# ------------------------------------------------------
#
#		Copyright 2025 IHP PDK Authors
#
#		Licensed under the Apache License, Version 2.0 (the "License");
#		you may not use this file except in compliance with the License.
#		You may obtain a copy of the License at
#		
#		   https://www.apache.org/licenses/LICENSE-2.0
#		
#		Unless required by applicable law or agreed to in writing, software
#		distributed under the License is distributed on an "AS IS" BASIS,
#		WITHOUT WARRANTIES OR CONDITIONS OF ANY KIND, either express or implied.
#		See the License for the specific language governing permissions and
#		limitations under the License.
#		
#		Generated on Thu Jul 30 11:38:32 2026		
#
# ------------------------------------------------------ 
VERSION 5.7 ;
BUSBITCHARS "[]" ;
DIVIDERCHAR "/" ;

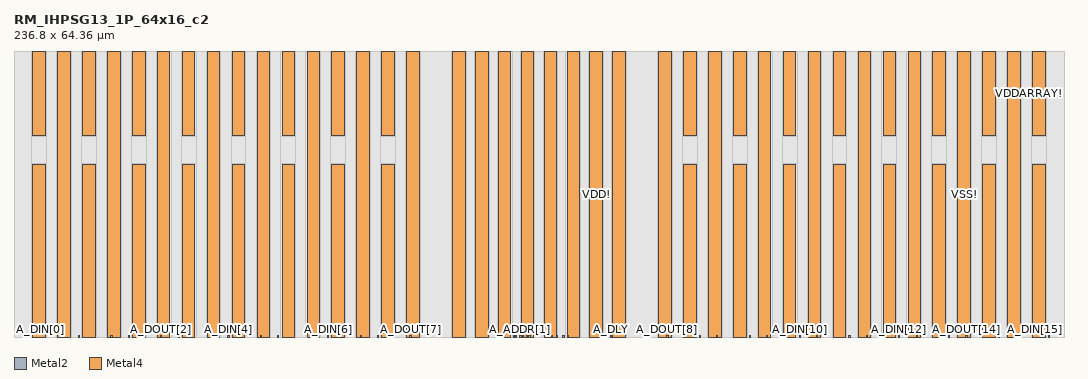
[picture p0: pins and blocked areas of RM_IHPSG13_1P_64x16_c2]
MACRO RM_IHPSG13_1P_64x16_c2
  CLASS BLOCK ;
  ORIGIN 0 0 ;
  FOREIGN RM_IHPSG13_1P_64x16_c2 0 0 ;
  SIZE 236.8 BY 64.36 ;
  SYMMETRY X Y R90 ;
  PIN A_DIN[8]
    DIRECTION INPUT ;
    USE SIGNAL ;
    ANTENNAPARTIALMETALAREA 1.794 LAYER Metal2 ;
    ANTENNAMODEL OXIDE1 ;
      ANTENNAGATEAREA 0.20085 LAYER Metal2 ;
      ANTENNAMAXAREACAR 9.838188 LAYER Metal2 ;
    PORT
      LAYER Metal2 ;
        RECT 154.57 0 154.83 0.26 ;
    END
  END A_DIN[8]
  PIN A_DIN[7]
    DIRECTION INPUT ;
    USE SIGNAL ;
    ANTENNAPARTIALMETALAREA 1.794 LAYER Metal2 ;
    ANTENNAMODEL OXIDE1 ;
      ANTENNAGATEAREA 0.20085 LAYER Metal2 ;
      ANTENNAMAXAREACAR 9.838188 LAYER Metal2 ;
    PORT
      LAYER Metal2 ;
        RECT 81.97 0 82.23 0.26 ;
    END
  END A_DIN[7]
  PIN A_DOUT[8]
    DIRECTION OUTPUT ;
    USE SIGNAL ;
    ANTENNAPARTIALMETALAREA 3.7095 LAYER Metal2 ;
    ANTENNADIFFAREA 0.988 LAYER Metal2 ;
    PORT
      LAYER Metal2 ;
        RECT 147.24 0 147.5 0.26 ;
    END
  END A_DOUT[8]
  PIN A_DOUT[7]
    DIRECTION OUTPUT ;
    USE SIGNAL ;
    ANTENNAPARTIALMETALAREA 3.7095 LAYER Metal2 ;
    ANTENNADIFFAREA 0.988 LAYER Metal2 ;
    PORT
      LAYER Metal2 ;
        RECT 89.3 0 89.56 0.26 ;
    END
  END A_DOUT[7]
  PIN VSS!
    DIRECTION INOUT ;
    USE GROUND ;
    NETEXPR "vss VSS!" ;
    PORT
      LAYER Metal4 ;
        RECT 224.11 0 226.92 64.36 ;
    END
    PORT
      LAYER Metal4 ;
        RECT 212.87 0 215.68 64.36 ;
    END
    PORT
      LAYER Metal4 ;
        RECT 201.63 0 204.44 64.36 ;
    END
    PORT
      LAYER Metal4 ;
        RECT 190.39 0 193.2 64.36 ;
    END
    PORT
      LAYER Metal4 ;
        RECT 179.15 0 181.96 64.36 ;
    END
    PORT
      LAYER Metal4 ;
        RECT 167.91 0 170.72 64.36 ;
    END
    PORT
      LAYER Metal4 ;
        RECT 156.67 0 159.48 64.36 ;
    END
    PORT
      LAYER Metal4 ;
        RECT 145.43 0 148.24 64.36 ;
    END
    PORT
      LAYER Metal4 ;
        RECT 135.02 0 137.83 64.36 ;
    END
    PORT
      LAYER Metal4 ;
        RECT 124.72 0 127.53 64.36 ;
    END
    PORT
      LAYER Metal4 ;
        RECT 109.27 0 112.08 64.36 ;
    END
    PORT
      LAYER Metal4 ;
        RECT 98.97 0 101.78 64.36 ;
    END
    PORT
      LAYER Metal4 ;
        RECT 88.56 0 91.37 64.36 ;
    END
    PORT
      LAYER Metal4 ;
        RECT 77.32 0 80.13 64.36 ;
    END
    PORT
      LAYER Metal4 ;
        RECT 66.08 0 68.89 64.36 ;
    END
    PORT
      LAYER Metal4 ;
        RECT 54.84 0 57.65 64.36 ;
    END
    PORT
      LAYER Metal4 ;
        RECT 43.6 0 46.41 64.36 ;
    END
    PORT
      LAYER Metal4 ;
        RECT 32.36 0 35.17 64.36 ;
    END
    PORT
      LAYER Metal4 ;
        RECT 21.12 0 23.93 64.36 ;
    END
    PORT
      LAYER Metal4 ;
        RECT 9.88 0 12.69 64.36 ;
    END
  END VSS!
  PIN VDD!
    DIRECTION INOUT ;
    USE POWER ;
    NETEXPR "vdd VDD!" ;
    PORT
      LAYER Metal4 ;
        RECT 229.73 0 232.54 38.825 ;
    END
    PORT
      LAYER Metal4 ;
        RECT 218.49 0 221.3 38.825 ;
    END
    PORT
      LAYER Metal4 ;
        RECT 207.25 0 210.06 38.825 ;
    END
    PORT
      LAYER Metal4 ;
        RECT 196.01 0 198.82 38.825 ;
    END
    PORT
      LAYER Metal4 ;
        RECT 184.77 0 187.58 38.825 ;
    END
    PORT
      LAYER Metal4 ;
        RECT 173.53 0 176.34 38.825 ;
    END
    PORT
      LAYER Metal4 ;
        RECT 162.29 0 165.1 38.825 ;
    END
    PORT
      LAYER Metal4 ;
        RECT 151.05 0 153.86 38.825 ;
    END
    PORT
      LAYER Metal4 ;
        RECT 129.87 0 132.68 64.36 ;
    END
    PORT
      LAYER Metal4 ;
        RECT 119.57 0 122.38 64.36 ;
    END
    PORT
      LAYER Metal4 ;
        RECT 114.42 0 117.23 64.36 ;
    END
    PORT
      LAYER Metal4 ;
        RECT 104.12 0 106.93 64.36 ;
    END
    PORT
      LAYER Metal4 ;
        RECT 82.94 0 85.75 38.825 ;
    END
    PORT
      LAYER Metal4 ;
        RECT 71.7 0 74.51 38.825 ;
    END
    PORT
      LAYER Metal4 ;
        RECT 60.46 0 63.27 38.825 ;
    END
    PORT
      LAYER Metal4 ;
        RECT 49.22 0 52.03 38.825 ;
    END
    PORT
      LAYER Metal4 ;
        RECT 37.98 0 40.79 38.825 ;
    END
    PORT
      LAYER Metal4 ;
        RECT 26.74 0 29.55 38.825 ;
    END
    PORT
      LAYER Metal4 ;
        RECT 15.5 0 18.31 38.825 ;
    END
    PORT
      LAYER Metal4 ;
        RECT 4.26 0 7.07 38.825 ;
    END
  END VDD!
  PIN VDDARRAY!
    DIRECTION INOUT ;
    USE POWER ;
    NETEXPR "vddarray VDDARRAY!" ;
    PORT
      LAYER Metal4 ;
        RECT 229.73 45.465 232.54 64.36 ;
    END
    PORT
      LAYER Metal4 ;
        RECT 218.49 45.465 221.3 64.36 ;
    END
    PORT
      LAYER Metal4 ;
        RECT 207.25 45.465 210.06 64.36 ;
    END
    PORT
      LAYER Metal4 ;
        RECT 196.01 45.465 198.82 64.36 ;
    END
    PORT
      LAYER Metal4 ;
        RECT 184.77 45.465 187.58 64.36 ;
    END
    PORT
      LAYER Metal4 ;
        RECT 173.53 45.465 176.34 64.36 ;
    END
    PORT
      LAYER Metal4 ;
        RECT 162.29 45.465 165.1 64.36 ;
    END
    PORT
      LAYER Metal4 ;
        RECT 151.05 45.465 153.86 64.36 ;
    END
    PORT
      LAYER Metal4 ;
        RECT 82.94 45.465 85.75 64.36 ;
    END
    PORT
      LAYER Metal4 ;
        RECT 71.7 45.465 74.51 64.36 ;
    END
    PORT
      LAYER Metal4 ;
        RECT 60.46 45.465 63.27 64.36 ;
    END
    PORT
      LAYER Metal4 ;
        RECT 49.22 45.465 52.03 64.36 ;
    END
    PORT
      LAYER Metal4 ;
        RECT 37.98 45.465 40.79 64.36 ;
    END
    PORT
      LAYER Metal4 ;
        RECT 26.74 45.465 29.55 64.36 ;
    END
    PORT
      LAYER Metal4 ;
        RECT 15.5 45.465 18.31 64.36 ;
    END
    PORT
      LAYER Metal4 ;
        RECT 4.26 45.465 7.07 64.36 ;
    END
  END VDDARRAY!
  PIN A_DIN[9]
    DIRECTION INPUT ;
    USE SIGNAL ;
    ANTENNAPARTIALMETALAREA 1.794 LAYER Metal2 ;
    ANTENNAMODEL OXIDE1 ;
      ANTENNAGATEAREA 0.20085 LAYER Metal2 ;
      ANTENNAMAXAREACAR 9.838188 LAYER Metal2 ;
    PORT
      LAYER Metal2 ;
        RECT 165.81 0 166.07 0.26 ;
    END
  END A_DIN[9]
  PIN A_DIN[6]
    DIRECTION INPUT ;
    USE SIGNAL ;
    ANTENNAPARTIALMETALAREA 1.794 LAYER Metal2 ;
    ANTENNAMODEL OXIDE1 ;
      ANTENNAGATEAREA 0.20085 LAYER Metal2 ;
      ANTENNAMAXAREACAR 9.838188 LAYER Metal2 ;
    PORT
      LAYER Metal2 ;
        RECT 70.73 0 70.99 0.26 ;
    END
  END A_DIN[6]
  PIN A_DOUT[9]
    DIRECTION OUTPUT ;
    USE SIGNAL ;
    ANTENNAPARTIALMETALAREA 3.7095 LAYER Metal2 ;
    ANTENNADIFFAREA 0.988 LAYER Metal2 ;
    PORT
      LAYER Metal2 ;
        RECT 158.48 0 158.74 0.26 ;
    END
  END A_DOUT[9]
  PIN A_DOUT[6]
    DIRECTION OUTPUT ;
    USE SIGNAL ;
    ANTENNAPARTIALMETALAREA 3.7095 LAYER Metal2 ;
    ANTENNADIFFAREA 0.988 LAYER Metal2 ;
    PORT
      LAYER Metal2 ;
        RECT 78.06 0 78.32 0.26 ;
    END
  END A_DOUT[6]
  PIN A_DIN[10]
    DIRECTION INPUT ;
    USE SIGNAL ;
    ANTENNAPARTIALMETALAREA 1.794 LAYER Metal2 ;
    ANTENNAMODEL OXIDE1 ;
      ANTENNAGATEAREA 0.20085 LAYER Metal2 ;
      ANTENNAMAXAREACAR 9.838188 LAYER Metal2 ;
    PORT
      LAYER Metal2 ;
        RECT 177.05 0 177.31 0.26 ;
    END
  END A_DIN[10]
  PIN A_DIN[5]
    DIRECTION INPUT ;
    USE SIGNAL ;
    ANTENNAPARTIALMETALAREA 1.794 LAYER Metal2 ;
    ANTENNAMODEL OXIDE1 ;
      ANTENNAGATEAREA 0.20085 LAYER Metal2 ;
      ANTENNAMAXAREACAR 9.838188 LAYER Metal2 ;
    PORT
      LAYER Metal2 ;
        RECT 59.49 0 59.75 0.26 ;
    END
  END A_DIN[5]
  PIN A_DOUT[10]
    DIRECTION OUTPUT ;
    USE SIGNAL ;
    ANTENNAPARTIALMETALAREA 3.7095 LAYER Metal2 ;
    ANTENNADIFFAREA 0.988 LAYER Metal2 ;
    PORT
      LAYER Metal2 ;
        RECT 169.72 0 169.98 0.26 ;
    END
  END A_DOUT[10]
  PIN A_DOUT[5]
    DIRECTION OUTPUT ;
    USE SIGNAL ;
    ANTENNAPARTIALMETALAREA 3.7095 LAYER Metal2 ;
    ANTENNADIFFAREA 0.988 LAYER Metal2 ;
    PORT
      LAYER Metal2 ;
        RECT 66.82 0 67.08 0.26 ;
    END
  END A_DOUT[5]
  PIN A_DIN[11]
    DIRECTION INPUT ;
    USE SIGNAL ;
    ANTENNAPARTIALMETALAREA 1.794 LAYER Metal2 ;
    ANTENNAMODEL OXIDE1 ;
      ANTENNAGATEAREA 0.20085 LAYER Metal2 ;
      ANTENNAMAXAREACAR 9.838188 LAYER Metal2 ;
    PORT
      LAYER Metal2 ;
        RECT 188.29 0 188.55 0.26 ;
    END
  END A_DIN[11]
  PIN A_DIN[4]
    DIRECTION INPUT ;
    USE SIGNAL ;
    ANTENNAPARTIALMETALAREA 1.794 LAYER Metal2 ;
    ANTENNAMODEL OXIDE1 ;
      ANTENNAGATEAREA 0.20085 LAYER Metal2 ;
      ANTENNAMAXAREACAR 9.838188 LAYER Metal2 ;
    PORT
      LAYER Metal2 ;
        RECT 48.25 0 48.51 0.26 ;
    END
  END A_DIN[4]
  PIN A_DOUT[11]
    DIRECTION OUTPUT ;
    USE SIGNAL ;
    ANTENNAPARTIALMETALAREA 3.7095 LAYER Metal2 ;
    ANTENNADIFFAREA 0.988 LAYER Metal2 ;
    PORT
      LAYER Metal2 ;
        RECT 180.96 0 181.22 0.26 ;
    END
  END A_DOUT[11]
  PIN A_DOUT[4]
    DIRECTION OUTPUT ;
    USE SIGNAL ;
    ANTENNAPARTIALMETALAREA 3.7095 LAYER Metal2 ;
    ANTENNADIFFAREA 0.988 LAYER Metal2 ;
    PORT
      LAYER Metal2 ;
        RECT 55.58 0 55.84 0.26 ;
    END
  END A_DOUT[4]
  PIN A_DIN[12]
    DIRECTION INPUT ;
    USE SIGNAL ;
    ANTENNAPARTIALMETALAREA 1.794 LAYER Metal2 ;
    ANTENNAMODEL OXIDE1 ;
      ANTENNAGATEAREA 0.20085 LAYER Metal2 ;
      ANTENNAMAXAREACAR 9.838188 LAYER Metal2 ;
    PORT
      LAYER Metal2 ;
        RECT 199.53 0 199.79 0.26 ;
    END
  END A_DIN[12]
  PIN A_DIN[3]
    DIRECTION INPUT ;
    USE SIGNAL ;
    ANTENNAPARTIALMETALAREA 1.794 LAYER Metal2 ;
    ANTENNAMODEL OXIDE1 ;
      ANTENNAGATEAREA 0.20085 LAYER Metal2 ;
      ANTENNAMAXAREACAR 9.838188 LAYER Metal2 ;
    PORT
      LAYER Metal2 ;
        RECT 37.01 0 37.27 0.26 ;
    END
  END A_DIN[3]
  PIN A_DOUT[12]
    DIRECTION OUTPUT ;
    USE SIGNAL ;
    ANTENNAPARTIALMETALAREA 3.7095 LAYER Metal2 ;
    ANTENNADIFFAREA 0.988 LAYER Metal2 ;
    PORT
      LAYER Metal2 ;
        RECT 192.2 0 192.46 0.26 ;
    END
  END A_DOUT[12]
  PIN A_DOUT[3]
    DIRECTION OUTPUT ;
    USE SIGNAL ;
    ANTENNAPARTIALMETALAREA 3.7095 LAYER Metal2 ;
    ANTENNADIFFAREA 0.988 LAYER Metal2 ;
    PORT
      LAYER Metal2 ;
        RECT 44.34 0 44.6 0.26 ;
    END
  END A_DOUT[3]
  PIN A_DIN[13]
    DIRECTION INPUT ;
    USE SIGNAL ;
    ANTENNAPARTIALMETALAREA 1.794 LAYER Metal2 ;
    ANTENNAMODEL OXIDE1 ;
      ANTENNAGATEAREA 0.20085 LAYER Metal2 ;
      ANTENNAMAXAREACAR 9.838188 LAYER Metal2 ;
    PORT
      LAYER Metal2 ;
        RECT 210.77 0 211.03 0.26 ;
    END
  END A_DIN[13]
  PIN A_DIN[2]
    DIRECTION INPUT ;
    USE SIGNAL ;
    ANTENNAPARTIALMETALAREA 1.794 LAYER Metal2 ;
    ANTENNAMODEL OXIDE1 ;
      ANTENNAGATEAREA 0.20085 LAYER Metal2 ;
      ANTENNAMAXAREACAR 9.838188 LAYER Metal2 ;
    PORT
      LAYER Metal2 ;
        RECT 25.77 0 26.03 0.26 ;
    END
  END A_DIN[2]
  PIN A_DOUT[13]
    DIRECTION OUTPUT ;
    USE SIGNAL ;
    ANTENNAPARTIALMETALAREA 3.7095 LAYER Metal2 ;
    ANTENNADIFFAREA 0.988 LAYER Metal2 ;
    PORT
      LAYER Metal2 ;
        RECT 203.44 0 203.7 0.26 ;
    END
  END A_DOUT[13]
  PIN A_DOUT[2]
    DIRECTION OUTPUT ;
    USE SIGNAL ;
    ANTENNAPARTIALMETALAREA 3.7095 LAYER Metal2 ;
    ANTENNADIFFAREA 0.988 LAYER Metal2 ;
    PORT
      LAYER Metal2 ;
        RECT 33.1 0 33.36 0.26 ;
    END
  END A_DOUT[2]
  PIN A_DIN[14]
    DIRECTION INPUT ;
    USE SIGNAL ;
    ANTENNAPARTIALMETALAREA 1.794 LAYER Metal2 ;
    ANTENNAMODEL OXIDE1 ;
      ANTENNAGATEAREA 0.20085 LAYER Metal2 ;
      ANTENNAMAXAREACAR 9.838188 LAYER Metal2 ;
    PORT
      LAYER Metal2 ;
        RECT 222.01 0 222.27 0.26 ;
    END
  END A_DIN[14]
  PIN A_DIN[1]
    DIRECTION INPUT ;
    USE SIGNAL ;
    ANTENNAPARTIALMETALAREA 1.794 LAYER Metal2 ;
    ANTENNAMODEL OXIDE1 ;
      ANTENNAGATEAREA 0.20085 LAYER Metal2 ;
      ANTENNAMAXAREACAR 9.838188 LAYER Metal2 ;
    PORT
      LAYER Metal2 ;
        RECT 14.53 0 14.79 0.26 ;
    END
  END A_DIN[1]
  PIN A_DOUT[14]
    DIRECTION OUTPUT ;
    USE SIGNAL ;
    ANTENNAPARTIALMETALAREA 3.7095 LAYER Metal2 ;
    ANTENNADIFFAREA 0.988 LAYER Metal2 ;
    PORT
      LAYER Metal2 ;
        RECT 214.68 0 214.94 0.26 ;
    END
  END A_DOUT[14]
  PIN A_DOUT[1]
    DIRECTION OUTPUT ;
    USE SIGNAL ;
    ANTENNAPARTIALMETALAREA 3.7095 LAYER Metal2 ;
    ANTENNADIFFAREA 0.988 LAYER Metal2 ;
    PORT
      LAYER Metal2 ;
        RECT 21.86 0 22.12 0.26 ;
    END
  END A_DOUT[1]
  PIN A_DIN[15]
    DIRECTION INPUT ;
    USE SIGNAL ;
    ANTENNAPARTIALMETALAREA 1.794 LAYER Metal2 ;
    ANTENNAMODEL OXIDE1 ;
      ANTENNAGATEAREA 0.20085 LAYER Metal2 ;
      ANTENNAMAXAREACAR 9.838188 LAYER Metal2 ;
    PORT
      LAYER Metal2 ;
        RECT 233.25 0 233.51 0.26 ;
    END
  END A_DIN[15]
  PIN A_DIN[0]
    DIRECTION INPUT ;
    USE SIGNAL ;
    ANTENNAPARTIALMETALAREA 1.794 LAYER Metal2 ;
    ANTENNAMODEL OXIDE1 ;
      ANTENNAGATEAREA 0.20085 LAYER Metal2 ;
      ANTENNAMAXAREACAR 9.838188 LAYER Metal2 ;
    PORT
      LAYER Metal2 ;
        RECT 3.29 0 3.55 0.26 ;
    END
  END A_DIN[0]
  PIN A_DOUT[15]
    DIRECTION OUTPUT ;
    USE SIGNAL ;
    ANTENNAPARTIALMETALAREA 3.7095 LAYER Metal2 ;
    ANTENNADIFFAREA 0.988 LAYER Metal2 ;
    PORT
      LAYER Metal2 ;
        RECT 225.92 0 226.18 0.26 ;
    END
  END A_DOUT[15]
  PIN A_DOUT[0]
    DIRECTION OUTPUT ;
    USE SIGNAL ;
    ANTENNAPARTIALMETALAREA 3.7095 LAYER Metal2 ;
    ANTENNADIFFAREA 0.988 LAYER Metal2 ;
    PORT
      LAYER Metal2 ;
        RECT 10.62 0 10.88 0.26 ;
    END
  END A_DOUT[0]
  PIN A_ADDR[0]
    DIRECTION INPUT ;
    USE SIGNAL ;
    ANTENNAPARTIALMETALAREA 8.9011 LAYER Metal2 ;
    ANTENNAMODEL OXIDE1 ;
      ANTENNAGATEAREA 0.20085 LAYER Metal2 ;
      ANTENNAMAXAREACAR 45.223301 LAYER Metal2 ;
    PORT
      LAYER Metal2 ;
        RECT 114.6 0 114.86 0.26 ;
    END
  END A_ADDR[0]
  PIN A_ADDR[1]
    DIRECTION INPUT ;
    USE SIGNAL ;
    ANTENNAPARTIALMETALAREA 7.774 LAYER Metal2 ;
    ANTENNAMODEL OXIDE1 ;
      ANTENNAGATEAREA 0.20085 LAYER Metal2 ;
      ANTENNAMAXAREACAR 39.656958 LAYER Metal2 ;
    PORT
      LAYER Metal2 ;
        RECT 114.09 0 114.35 0.26 ;
    END
  END A_ADDR[1]
  PIN A_ADDR[2]
    DIRECTION INPUT ;
    USE SIGNAL ;
    ANTENNAPARTIALMETALAREA 10.6327 LAYER Metal2 ;
    ANTENNAPARTIALMETALAREA 1.5246 LAYER Metal3 ;
    ANTENNAPARTIALCUTAREA 0.0722 LAYER Via2 ;
    ANTENNAMODEL OXIDE1 ;
      ANTENNAGATEAREA 0.20085 LAYER Metal3 ;
      ANTENNAMAXAREACAR 9.415982 LAYER Metal3 ;
    PORT
      LAYER Metal2 ;
        RECT 122.25 0 122.51 0.26 ;
    END
  END A_ADDR[2]
  PIN A_ADDR[3]
    DIRECTION INPUT ;
    USE SIGNAL ;
    ANTENNAPARTIALMETALAREA 10.6327 LAYER Metal2 ;
    ANTENNAPARTIALMETALAREA 3.8367 LAYER Metal3 ;
    ANTENNAPARTIALCUTAREA 0.0722 LAYER Via2 ;
    ANTENNAMODEL OXIDE1 ;
      ANTENNAGATEAREA 0.20085 LAYER Metal3 ;
      ANTENNAMAXAREACAR 20.927558 LAYER Metal3 ;
    PORT
      LAYER Metal2 ;
        RECT 121.23 0 121.49 0.26 ;
    END
  END A_ADDR[3]
  PIN A_ADDR[4]
    DIRECTION INPUT ;
    USE SIGNAL ;
    ANTENNAPARTIALMETALAREA 12.1979 LAYER Metal2 ;
    ANTENNAMODEL OXIDE1 ;
      ANTENNAGATEAREA 0.20085 LAYER Metal2 ;
      ANTENNAMAXAREACAR 61.63754 LAYER Metal2 ;
    PORT
      LAYER Metal2 ;
        RECT 124.8 0 125.06 0.26 ;
    END
  END A_ADDR[4]
  PIN A_ADDR[5]
    DIRECTION INPUT ;
    USE SIGNAL ;
    ANTENNAPARTIALMETALAREA 13.9269 LAYER Metal2 ;
    ANTENNAMODEL OXIDE1 ;
      ANTENNAGATEAREA 0.20085 LAYER Metal2 ;
      ANTENNAMAXAREACAR 70.245955 LAYER Metal2 ;
    PORT
      LAYER Metal2 ;
        RECT 123.78 0 124.04 0.26 ;
    END
  END A_ADDR[5]
  PIN A_CLK
    DIRECTION INPUT ;
    USE SIGNAL ;
    ANTENNAPARTIALMETALAREA 4.0547 LAYER Metal2 ;
    ANTENNAMODEL OXIDE1 ;
      ANTENNAGATEAREA 0.20085 LAYER Metal2 ;
      ANTENNAMAXAREACAR 21.093851 LAYER Metal2 ;
    PORT
      LAYER Metal2 ;
        RECT 112.56 0 112.82 0.26 ;
    END
  END A_CLK
  PIN A_REN
    DIRECTION INPUT ;
    USE SIGNAL ;
    ANTENNAPARTIALMETALAREA 3.99505 LAYER Metal2 ;
    ANTENNAMODEL OXIDE1 ;
      ANTENNAGATEAREA 0.20085 LAYER Metal2 ;
      ANTENNAMAXAREACAR 20.796863 LAYER Metal2 ;
    PORT
      LAYER Metal2 ;
        RECT 116.13 0 116.39 0.26 ;
    END
  END A_REN
  PIN A_WEN
    DIRECTION INPUT ;
    USE SIGNAL ;
    ANTENNAPARTIALMETALAREA 2.8847 LAYER Metal2 ;
    ANTENNAMODEL OXIDE1 ;
      ANTENNAGATEAREA 0.20085 LAYER Metal2 ;
      ANTENNAMAXAREACAR 15.268608 LAYER Metal2 ;
    PORT
      LAYER Metal2 ;
        RECT 115.62 0 115.88 0.26 ;
    END
  END A_WEN
  PIN A_MEN
    DIRECTION INPUT ;
    USE SIGNAL ;
    ANTENNAPARTIALMETALAREA 3.0247 LAYER Metal2 ;
    ANTENNAMODEL OXIDE1 ;
      ANTENNAGATEAREA 0.20085 LAYER Metal2 ;
      ANTENNAMAXAREACAR 15.965646 LAYER Metal2 ;
    PORT
      LAYER Metal2 ;
        RECT 113.07 0 113.33 0.26 ;
    END
  END A_MEN
  PIN A_DLY
    DIRECTION INPUT ;
    USE SIGNAL ;
    ANTENNAPARTIALMETALAREA 6.058 LAYER Metal2 ;
    ANTENNAMODEL OXIDE1 ;
      ANTENNAGATEAREA 0.3367 LAYER Metal2 ;
      ANTENNAMAXAREACAR 18.532819 LAYER Metal2 ;
    PORT
      LAYER Metal2 ;
        RECT 134.49 0 134.75 0.26 ;
    END
  END A_DLY
  OBS
    LAYER Metal1 ;
      RECT 0 0 236.8 64.36 ;
    LAYER Metal2 ;
      RECT 0.105 45.465 0.305 64.335 ;
      RECT 1.1 63.605 1.3 64.335 ;
      RECT 3.29 0.52 3.55 5.16 ;
      RECT 2.77 4.9 3.55 5.16 ;
      RECT 2.77 4.9 3.03 6.64 ;
      RECT 1.92 63.605 2.12 64.335 ;
      RECT 2.415 63.605 2.615 64.335 ;
      RECT 2.915 63.605 3.115 64.335 ;
      RECT 3.415 63.605 3.615 64.335 ;
      RECT 4.655 0.17 5.425 0.94 ;
      RECT 4.655 0.17 4.915 12.9 ;
      RECT 5.165 0.17 5.425 12.9 ;
      RECT 3.91 63.605 4.11 64.335 ;
      RECT 4.73 63.605 4.93 64.335 ;
      RECT 5.675 0.17 6.445 0.43 ;
      RECT 5.675 0.17 5.935 11.5 ;
      RECT 6.185 0.17 6.445 11.5 ;
      RECT 5.225 63.605 5.425 64.335 ;
      RECT 5.725 63.605 5.925 64.335 ;
      RECT 6.225 63.605 6.425 64.335 ;
      RECT 7.715 0.17 8.485 0.43 ;
      RECT 7.715 0.17 7.975 10.48 ;
      RECT 8.225 0.17 8.485 10.99 ;
      RECT 6.72 63.605 6.92 64.335 ;
      RECT 7.54 63.605 7.74 64.335 ;
      RECT 8.735 0.17 9.505 0.94 ;
      RECT 8.735 0.17 8.995 8.7 ;
      RECT 9.245 0.17 9.505 12.9 ;
      RECT 8.035 63.605 8.235 64.335 ;
      RECT 8.535 63.605 8.735 64.335 ;
      RECT 9.035 63.605 9.235 64.335 ;
      RECT 9.53 63.605 9.73 64.335 ;
      RECT 10.35 63.605 10.55 64.335 ;
      RECT 10.62 0.52 10.88 14.11 ;
      RECT 10.845 63.605 11.045 64.335 ;
      RECT 11.345 63.605 11.545 64.335 ;
      RECT 11.845 63.605 12.045 64.335 ;
      RECT 12.34 63.605 12.54 64.335 ;
      RECT 14.53 0.52 14.79 5.16 ;
      RECT 14.01 4.9 14.79 5.16 ;
      RECT 14.01 4.9 14.27 6.64 ;
      RECT 13.16 63.605 13.36 64.335 ;
      RECT 13.655 63.605 13.855 64.335 ;
      RECT 14.155 63.605 14.355 64.335 ;
      RECT 14.655 63.605 14.855 64.335 ;
      RECT 15.895 0.17 16.665 0.94 ;
      RECT 15.895 0.17 16.155 12.9 ;
      RECT 16.405 0.17 16.665 12.9 ;
      RECT 15.15 63.605 15.35 64.335 ;
      RECT 15.97 63.605 16.17 64.335 ;
      RECT 16.915 0.17 17.685 0.43 ;
      RECT 16.915 0.17 17.175 11.5 ;
      RECT 17.425 0.17 17.685 11.5 ;
      RECT 16.465 63.605 16.665 64.335 ;
      RECT 16.965 63.605 17.165 64.335 ;
      RECT 17.465 63.605 17.665 64.335 ;
      RECT 18.955 0.17 19.725 0.43 ;
      RECT 18.955 0.17 19.215 10.48 ;
      RECT 19.465 0.17 19.725 10.99 ;
      RECT 17.96 63.605 18.16 64.335 ;
      RECT 18.78 63.605 18.98 64.335 ;
      RECT 19.975 0.17 20.745 0.94 ;
      RECT 19.975 0.17 20.235 8.7 ;
      RECT 20.485 0.17 20.745 12.9 ;
      RECT 19.275 63.605 19.475 64.335 ;
      RECT 19.775 63.605 19.975 64.335 ;
      RECT 20.275 63.605 20.475 64.335 ;
      RECT 20.77 63.605 20.97 64.335 ;
      RECT 21.59 63.605 21.79 64.335 ;
      RECT 21.86 0.52 22.12 14.11 ;
      RECT 22.085 63.605 22.285 64.335 ;
      RECT 22.585 63.605 22.785 64.335 ;
      RECT 23.085 63.605 23.285 64.335 ;
      RECT 23.58 63.605 23.78 64.335 ;
      RECT 25.77 0.52 26.03 5.16 ;
      RECT 25.25 4.9 26.03 5.16 ;
      RECT 25.25 4.9 25.51 6.64 ;
      RECT 24.4 63.605 24.6 64.335 ;
      RECT 24.895 63.605 25.095 64.335 ;
      RECT 25.395 63.605 25.595 64.335 ;
      RECT 25.895 63.605 26.095 64.335 ;
      RECT 27.135 0.17 27.905 0.94 ;
      RECT 27.135 0.17 27.395 12.9 ;
      RECT 27.645 0.17 27.905 12.9 ;
      RECT 26.39 63.605 26.59 64.335 ;
      RECT 27.21 63.605 27.41 64.335 ;
      RECT 28.155 0.17 28.925 0.43 ;
      RECT 28.155 0.17 28.415 11.5 ;
      RECT 28.665 0.17 28.925 11.5 ;
      RECT 27.705 63.605 27.905 64.335 ;
      RECT 28.205 63.605 28.405 64.335 ;
      RECT 28.705 63.605 28.905 64.335 ;
      RECT 30.195 0.17 30.965 0.43 ;
      RECT 30.195 0.17 30.455 10.48 ;
      RECT 30.705 0.17 30.965 10.99 ;
      RECT 29.2 63.605 29.4 64.335 ;
      RECT 30.02 63.605 30.22 64.335 ;
      RECT 31.215 0.17 31.985 0.94 ;
      RECT 31.215 0.17 31.475 8.7 ;
      RECT 31.725 0.17 31.985 12.9 ;
      RECT 30.515 63.605 30.715 64.335 ;
      RECT 31.015 63.605 31.215 64.335 ;
      RECT 31.515 63.605 31.715 64.335 ;
      RECT 32.01 63.605 32.21 64.335 ;
      RECT 32.83 63.605 33.03 64.335 ;
      RECT 33.1 0.52 33.36 14.11 ;
      RECT 33.325 63.605 33.525 64.335 ;
      RECT 33.825 63.605 34.025 64.335 ;
      RECT 34.325 63.605 34.525 64.335 ;
      RECT 34.82 63.605 35.02 64.335 ;
      RECT 37.01 0.52 37.27 5.16 ;
      RECT 36.49 4.9 37.27 5.16 ;
      RECT 36.49 4.9 36.75 6.64 ;
      RECT 35.64 63.605 35.84 64.335 ;
      RECT 36.135 63.605 36.335 64.335 ;
      RECT 36.635 63.605 36.835 64.335 ;
      RECT 37.135 63.605 37.335 64.335 ;
      RECT 38.375 0.17 39.145 0.94 ;
      RECT 38.375 0.17 38.635 12.9 ;
      RECT 38.885 0.17 39.145 12.9 ;
      RECT 37.63 63.605 37.83 64.335 ;
      RECT 38.45 63.605 38.65 64.335 ;
      RECT 39.395 0.17 40.165 0.43 ;
      RECT 39.395 0.17 39.655 11.5 ;
      RECT 39.905 0.17 40.165 11.5 ;
      RECT 38.945 63.605 39.145 64.335 ;
      RECT 39.445 63.605 39.645 64.335 ;
      RECT 39.945 63.605 40.145 64.335 ;
      RECT 41.435 0.17 42.205 0.43 ;
      RECT 41.435 0.17 41.695 10.48 ;
      RECT 41.945 0.17 42.205 10.99 ;
      RECT 40.44 63.605 40.64 64.335 ;
      RECT 41.26 63.605 41.46 64.335 ;
      RECT 42.455 0.17 43.225 0.94 ;
      RECT 42.455 0.17 42.715 8.7 ;
      RECT 42.965 0.17 43.225 12.9 ;
      RECT 41.755 63.605 41.955 64.335 ;
      RECT 42.255 63.605 42.455 64.335 ;
      RECT 42.755 63.605 42.955 64.335 ;
      RECT 43.25 63.605 43.45 64.335 ;
      RECT 44.07 63.605 44.27 64.335 ;
      RECT 44.34 0.52 44.6 14.11 ;
      RECT 44.565 63.605 44.765 64.335 ;
      RECT 45.065 63.605 45.265 64.335 ;
      RECT 45.565 63.605 45.765 64.335 ;
      RECT 46.06 63.605 46.26 64.335 ;
      RECT 48.25 0.52 48.51 5.16 ;
      RECT 47.73 4.9 48.51 5.16 ;
      RECT 47.73 4.9 47.99 6.64 ;
      RECT 46.88 63.605 47.08 64.335 ;
      RECT 47.375 63.605 47.575 64.335 ;
      RECT 47.875 63.605 48.075 64.335 ;
      RECT 48.375 63.605 48.575 64.335 ;
      RECT 49.615 0.17 50.385 0.94 ;
      RECT 49.615 0.17 49.875 12.9 ;
      RECT 50.125 0.17 50.385 12.9 ;
      RECT 48.87 63.605 49.07 64.335 ;
      RECT 49.69 63.605 49.89 64.335 ;
      RECT 50.635 0.17 51.405 0.43 ;
      RECT 50.635 0.17 50.895 11.5 ;
      RECT 51.145 0.17 51.405 11.5 ;
      RECT 50.185 63.605 50.385 64.335 ;
      RECT 50.685 63.605 50.885 64.335 ;
      RECT 51.185 63.605 51.385 64.335 ;
      RECT 52.675 0.17 53.445 0.43 ;
      RECT 52.675 0.17 52.935 10.48 ;
      RECT 53.185 0.17 53.445 10.99 ;
      RECT 51.68 63.605 51.88 64.335 ;
      RECT 52.5 63.605 52.7 64.335 ;
      RECT 53.695 0.17 54.465 0.94 ;
      RECT 53.695 0.17 53.955 8.7 ;
      RECT 54.205 0.17 54.465 12.9 ;
      RECT 52.995 63.605 53.195 64.335 ;
      RECT 53.495 63.605 53.695 64.335 ;
      RECT 53.995 63.605 54.195 64.335 ;
      RECT 54.49 63.605 54.69 64.335 ;
      RECT 55.31 63.605 55.51 64.335 ;
      RECT 55.58 0.52 55.84 14.11 ;
      RECT 55.805 63.605 56.005 64.335 ;
      RECT 56.305 63.605 56.505 64.335 ;
      RECT 56.805 63.605 57.005 64.335 ;
      RECT 57.3 63.605 57.5 64.335 ;
      RECT 59.49 0.52 59.75 5.16 ;
      RECT 58.97 4.9 59.75 5.16 ;
      RECT 58.97 4.9 59.23 6.64 ;
      RECT 58.12 63.605 58.32 64.335 ;
      RECT 58.615 63.605 58.815 64.335 ;
      RECT 59.115 63.605 59.315 64.335 ;
      RECT 59.615 63.605 59.815 64.335 ;
      RECT 60.855 0.17 61.625 0.94 ;
      RECT 60.855 0.17 61.115 12.9 ;
      RECT 61.365 0.17 61.625 12.9 ;
      RECT 60.11 63.605 60.31 64.335 ;
      RECT 60.93 63.605 61.13 64.335 ;
      RECT 61.875 0.17 62.645 0.43 ;
      RECT 61.875 0.17 62.135 11.5 ;
      RECT 62.385 0.17 62.645 11.5 ;
      RECT 61.425 63.605 61.625 64.335 ;
      RECT 61.925 63.605 62.125 64.335 ;
      RECT 62.425 63.605 62.625 64.335 ;
      RECT 63.915 0.17 64.685 0.43 ;
      RECT 63.915 0.17 64.175 10.48 ;
      RECT 64.425 0.17 64.685 10.99 ;
      RECT 62.92 63.605 63.12 64.335 ;
      RECT 63.74 63.605 63.94 64.335 ;
      RECT 64.935 0.17 65.705 0.94 ;
      RECT 64.935 0.17 65.195 8.7 ;
      RECT 65.445 0.17 65.705 12.9 ;
      RECT 64.235 63.605 64.435 64.335 ;
      RECT 64.735 63.605 64.935 64.335 ;
      RECT 65.235 63.605 65.435 64.335 ;
      RECT 65.73 63.605 65.93 64.335 ;
      RECT 66.55 63.605 66.75 64.335 ;
      RECT 66.82 0.52 67.08 14.11 ;
      RECT 67.045 63.605 67.245 64.335 ;
      RECT 67.545 63.605 67.745 64.335 ;
      RECT 68.045 63.605 68.245 64.335 ;
      RECT 68.54 63.605 68.74 64.335 ;
      RECT 70.73 0.52 70.99 5.16 ;
      RECT 70.21 4.9 70.99 5.16 ;
      RECT 70.21 4.9 70.47 6.64 ;
      RECT 69.36 63.605 69.56 64.335 ;
      RECT 69.855 63.605 70.055 64.335 ;
      RECT 70.355 63.605 70.555 64.335 ;
      RECT 70.855 63.605 71.055 64.335 ;
      RECT 72.095 0.17 72.865 0.94 ;
      RECT 72.095 0.17 72.355 12.9 ;
      RECT 72.605 0.17 72.865 12.9 ;
      RECT 71.35 63.605 71.55 64.335 ;
      RECT 72.17 63.605 72.37 64.335 ;
      RECT 73.115 0.17 73.885 0.43 ;
      RECT 73.115 0.17 73.375 11.5 ;
      RECT 73.625 0.17 73.885 11.5 ;
      RECT 72.665 63.605 72.865 64.335 ;
      RECT 73.165 63.605 73.365 64.335 ;
      RECT 73.665 63.605 73.865 64.335 ;
      RECT 75.155 0.17 75.925 0.43 ;
      RECT 75.155 0.17 75.415 10.48 ;
      RECT 75.665 0.17 75.925 10.99 ;
      RECT 74.16 63.605 74.36 64.335 ;
      RECT 74.98 63.605 75.18 64.335 ;
      RECT 76.175 0.17 76.945 0.94 ;
      RECT 76.175 0.17 76.435 8.7 ;
      RECT 76.685 0.17 76.945 12.9 ;
      RECT 75.475 63.605 75.675 64.335 ;
      RECT 75.975 63.605 76.175 64.335 ;
      RECT 76.475 63.605 76.675 64.335 ;
      RECT 76.97 63.605 77.17 64.335 ;
      RECT 77.79 63.605 77.99 64.335 ;
      RECT 78.06 0.52 78.32 14.11 ;
      RECT 78.285 63.605 78.485 64.335 ;
      RECT 78.785 63.605 78.985 64.335 ;
      RECT 79.285 63.605 79.485 64.335 ;
      RECT 79.78 63.605 79.98 64.335 ;
      RECT 81.97 0.52 82.23 5.16 ;
      RECT 81.45 4.9 82.23 5.16 ;
      RECT 81.45 4.9 81.71 6.64 ;
      RECT 80.6 63.605 80.8 64.335 ;
      RECT 81.095 63.605 81.295 64.335 ;
      RECT 81.595 63.605 81.795 64.335 ;
      RECT 82.095 63.605 82.295 64.335 ;
      RECT 83.335 0.17 84.105 0.94 ;
      RECT 83.335 0.17 83.595 12.9 ;
      RECT 83.845 0.17 84.105 12.9 ;
      RECT 82.59 63.605 82.79 64.335 ;
      RECT 83.41 63.605 83.61 64.335 ;
      RECT 84.355 0.17 85.125 0.43 ;
      RECT 84.355 0.17 84.615 11.5 ;
      RECT 84.865 0.17 85.125 11.5 ;
      RECT 83.905 63.605 84.105 64.335 ;
      RECT 84.405 63.605 84.605 64.335 ;
      RECT 84.905 63.605 85.105 64.335 ;
      RECT 86.395 0.17 87.165 0.43 ;
      RECT 86.395 0.17 86.655 10.48 ;
      RECT 86.905 0.17 87.165 10.99 ;
      RECT 85.4 63.605 85.6 64.335 ;
      RECT 86.22 63.605 86.42 64.335 ;
      RECT 87.415 0.17 88.185 0.94 ;
      RECT 87.415 0.17 87.675 8.7 ;
      RECT 87.925 0.17 88.185 12.9 ;
      RECT 86.715 63.605 86.915 64.335 ;
      RECT 87.215 63.605 87.415 64.335 ;
      RECT 87.715 63.605 87.915 64.335 ;
      RECT 88.21 63.605 88.41 64.335 ;
      RECT 89.03 63.605 89.23 64.335 ;
      RECT 89.3 0.52 89.56 14.11 ;
      RECT 89.525 63.605 89.725 64.335 ;
      RECT 90.025 63.605 90.225 64.335 ;
      RECT 90.525 63.605 90.725 64.335 ;
      RECT 92.515 0.17 93.285 0.43 ;
      RECT 92.515 0.17 92.775 8.7 ;
      RECT 93.025 0.17 93.285 8.7 ;
      RECT 93.535 0.17 94.305 0.94 ;
      RECT 93.535 0.17 93.795 8.7 ;
      RECT 94.045 0.17 94.305 8.7 ;
      RECT 94.555 0.17 95.325 0.43 ;
      RECT 94.555 0.17 94.815 8.7 ;
      RECT 95.065 0.17 95.325 8.7 ;
      RECT 95.575 0.17 96.345 0.94 ;
      RECT 95.575 0.17 95.835 8.7 ;
      RECT 96.085 0.17 96.345 8.7 ;
      RECT 96.595 0.17 97.365 0.43 ;
      RECT 96.595 0.17 96.855 8.7 ;
      RECT 97.105 0.17 97.365 8.7 ;
      RECT 97.615 0.17 98.385 0.94 ;
      RECT 97.615 0.17 97.875 8.7 ;
      RECT 98.125 0.17 98.385 8.7 ;
      RECT 91.02 63.605 91.22 64.335 ;
      RECT 91.84 63.605 92.04 64.335 ;
      RECT 92.835 63.605 93.035 64.335 ;
      RECT 100.32 0.17 101.09 0.94 ;
      RECT 100.32 0.17 100.58 8.7 ;
      RECT 100.83 0.17 101.09 8.7 ;
      RECT 98.79 0.3 99.05 8.7 ;
      RECT 99.3 0 99.56 8.7 ;
      RECT 99.81 0 100.07 8.7 ;
      RECT 101.34 0 101.6 8.7 ;
      RECT 101.85 0 102.11 8.7 ;
      RECT 102.36 0 102.62 8.7 ;
      RECT 102.87 0 103.13 8.7 ;
      RECT 103.38 0 103.64 8.7 ;
      RECT 105.42 0.17 106.19 0.94 ;
      RECT 105.42 0.17 105.68 8.7 ;
      RECT 105.93 0.17 106.19 8.7 ;
      RECT 106.44 0.17 107.21 0.43 ;
      RECT 106.44 0.17 106.7 8.7 ;
      RECT 106.95 0.17 107.21 8.7 ;
      RECT 103.89 0 104.15 8.7 ;
      RECT 104.4 0 104.66 8.7 ;
      RECT 104.91 0 105.17 8.7 ;
      RECT 107.46 0.3 107.72 8.7 ;
      RECT 107.97 0.3 108.23 8.7 ;
      RECT 110.01 0.17 110.78 0.94 ;
      RECT 110.01 0.17 110.27 8.7 ;
      RECT 110.52 0.17 110.78 8.7 ;
      RECT 108.48 0.3 108.74 8.7 ;
      RECT 108.99 0.3 109.25 8.7 ;
      RECT 109.5 0.3 109.76 8.7 ;
      RECT 111.03 0 111.29 8.7 ;
      RECT 111.54 0 111.8 8.7 ;
      RECT 112.05 0.3 112.31 8.7 ;
      RECT 112.56 0.52 112.82 8.7 ;
      RECT 113.07 0.52 113.33 8.7 ;
      RECT 113.58 0.3 113.84 8.7 ;
      RECT 114.09 0.52 114.35 8.7 ;
      RECT 114.6 0.52 114.86 8.7 ;
      RECT 115.11 0 115.37 8.7 ;
      RECT 115.62 0.52 115.88 8.7 ;
      RECT 116.13 0.52 116.39 8.7 ;
      RECT 116.64 0.3 116.9 8.7 ;
      RECT 117.15 0 117.41 8.7 ;
      RECT 117.66 0 117.92 8.7 ;
      RECT 118.17 0.3 118.43 8.7 ;
      RECT 120.21 0.17 120.98 0.94 ;
      RECT 120.21 0.17 120.47 8.7 ;
      RECT 120.72 0.17 120.98 8.7 ;
      RECT 118.68 0 118.94 8.7 ;
      RECT 119.19 0 119.45 8.7 ;
      RECT 119.7 0.3 119.96 8.7 ;
      RECT 121.23 0.52 121.49 8.7 ;
      RECT 121.74 0 122 8.7 ;
      RECT 122.25 0.52 122.51 8.7 ;
      RECT 122.76 0 123.02 8.7 ;
      RECT 123.27 0 123.53 8.7 ;
      RECT 123.78 0.52 124.04 8.7 ;
      RECT 124.29 0 124.55 8.7 ;
      RECT 126.33 0.17 127.1 0.94 ;
      RECT 126.33 0.17 126.59 8.7 ;
      RECT 126.84 0.17 127.1 8.7 ;
      RECT 124.8 0.52 125.06 8.7 ;
      RECT 125.31 0 125.57 8.7 ;
      RECT 125.82 0 126.08 8.7 ;
      RECT 127.35 0 127.61 8.7 ;
      RECT 129.39 0.17 130.16 0.43 ;
      RECT 129.39 0.17 129.65 8.7 ;
      RECT 129.9 0.17 130.16 8.7 ;
      RECT 127.86 0 128.12 8.7 ;
      RECT 128.37 0.3 128.63 8.7 ;
      RECT 128.88 0.3 129.14 8.7 ;
      RECT 130.41 0.3 130.67 8.7 ;
      RECT 130.92 0.3 131.18 8.7 ;
      RECT 131.43 0.3 131.69 8.7 ;
      RECT 131.94 0.3 132.2 8.7 ;
      RECT 132.45 0 132.71 8.7 ;
      RECT 132.96 0 133.22 8.7 ;
      RECT 135 0.17 135.77 0.43 ;
      RECT 135 0.17 135.26 8.7 ;
      RECT 135.51 0.17 135.77 8.7 ;
      RECT 136.02 0.17 136.79 0.94 ;
      RECT 136.02 0.17 136.28 25.5 ;
      RECT 136.53 0.17 136.79 33.9 ;
      RECT 137.04 0.17 137.81 0.43 ;
      RECT 137.04 0.17 137.3 8.7 ;
      RECT 137.55 0.17 137.81 8.7 ;
      RECT 138.415 0.17 139.185 0.94 ;
      RECT 138.415 0.17 138.675 8.7 ;
      RECT 138.925 0.17 139.185 8.7 ;
      RECT 139.435 0.17 140.205 0.43 ;
      RECT 139.435 0.17 139.695 8.7 ;
      RECT 139.945 0.17 140.205 8.7 ;
      RECT 140.455 0.17 141.225 0.94 ;
      RECT 140.455 0.17 140.715 8.7 ;
      RECT 140.965 0.17 141.225 8.7 ;
      RECT 141.475 0.17 142.245 0.43 ;
      RECT 141.475 0.17 141.735 8.7 ;
      RECT 141.985 0.17 142.245 8.7 ;
      RECT 142.495 0.17 143.265 0.94 ;
      RECT 142.495 0.17 142.755 8.7 ;
      RECT 143.005 0.17 143.265 8.7 ;
      RECT 133.47 0.3 133.73 8.7 ;
      RECT 143.515 0.17 144.285 0.43 ;
      RECT 143.515 0.17 143.775 8.7 ;
      RECT 144.025 0.17 144.285 8.7 ;
      RECT 133.98 0.3 134.24 8.7 ;
      RECT 134.49 0.52 134.75 8.7 ;
      RECT 143.765 63.605 143.965 64.335 ;
      RECT 144.76 63.605 144.96 64.335 ;
      RECT 145.58 63.605 145.78 64.335 ;
      RECT 146.075 63.605 146.275 64.335 ;
      RECT 146.575 63.605 146.775 64.335 ;
      RECT 147.075 63.605 147.275 64.335 ;
      RECT 147.24 0.52 147.5 14.11 ;
      RECT 148.615 0.17 149.385 0.94 ;
      RECT 149.125 0.17 149.385 8.7 ;
      RECT 148.615 0.17 148.875 12.9 ;
      RECT 147.57 63.605 147.77 64.335 ;
      RECT 148.39 63.605 148.59 64.335 ;
      RECT 149.635 0.17 150.405 0.43 ;
      RECT 150.145 0.17 150.405 10.48 ;
      RECT 149.635 0.17 149.895 10.99 ;
      RECT 148.885 63.605 149.085 64.335 ;
      RECT 149.385 63.605 149.585 64.335 ;
      RECT 149.885 63.605 150.085 64.335 ;
      RECT 150.38 63.605 150.58 64.335 ;
      RECT 151.675 0.17 152.445 0.43 ;
      RECT 151.675 0.17 151.935 11.5 ;
      RECT 152.185 0.17 152.445 11.5 ;
      RECT 151.2 63.605 151.4 64.335 ;
      RECT 151.695 63.605 151.895 64.335 ;
      RECT 152.695 0.17 153.465 0.94 ;
      RECT 152.695 0.17 152.955 12.9 ;
      RECT 153.205 0.17 153.465 12.9 ;
      RECT 152.195 63.605 152.395 64.335 ;
      RECT 152.695 63.605 152.895 64.335 ;
      RECT 153.19 63.605 153.39 64.335 ;
      RECT 154.57 0.52 154.83 5.16 ;
      RECT 154.57 4.9 155.35 5.16 ;
      RECT 155.09 4.9 155.35 6.64 ;
      RECT 154.01 63.605 154.21 64.335 ;
      RECT 154.505 63.605 154.705 64.335 ;
      RECT 155.005 63.605 155.205 64.335 ;
      RECT 155.505 63.605 155.705 64.335 ;
      RECT 156 63.605 156.2 64.335 ;
      RECT 156.82 63.605 157.02 64.335 ;
      RECT 157.315 63.605 157.515 64.335 ;
      RECT 157.815 63.605 158.015 64.335 ;
      RECT 158.315 63.605 158.515 64.335 ;
      RECT 158.48 0.52 158.74 14.11 ;
      RECT 159.855 0.17 160.625 0.94 ;
      RECT 160.365 0.17 160.625 8.7 ;
      RECT 159.855 0.17 160.115 12.9 ;
      RECT 158.81 63.605 159.01 64.335 ;
      RECT 159.63 63.605 159.83 64.335 ;
      RECT 160.875 0.17 161.645 0.43 ;
      RECT 161.385 0.17 161.645 10.48 ;
      RECT 160.875 0.17 161.135 10.99 ;
      RECT 160.125 63.605 160.325 64.335 ;
      RECT 160.625 63.605 160.825 64.335 ;
      RECT 161.125 63.605 161.325 64.335 ;
      RECT 161.62 63.605 161.82 64.335 ;
      RECT 162.915 0.17 163.685 0.43 ;
      RECT 162.915 0.17 163.175 11.5 ;
      RECT 163.425 0.17 163.685 11.5 ;
      RECT 162.44 63.605 162.64 64.335 ;
      RECT 162.935 63.605 163.135 64.335 ;
      RECT 163.935 0.17 164.705 0.94 ;
      RECT 163.935 0.17 164.195 12.9 ;
      RECT 164.445 0.17 164.705 12.9 ;
      RECT 163.435 63.605 163.635 64.335 ;
      RECT 163.935 63.605 164.135 64.335 ;
      RECT 164.43 63.605 164.63 64.335 ;
      RECT 165.81 0.52 166.07 5.16 ;
      RECT 165.81 4.9 166.59 5.16 ;
      RECT 166.33 4.9 166.59 6.64 ;
      RECT 165.25 63.605 165.45 64.335 ;
      RECT 165.745 63.605 165.945 64.335 ;
      RECT 166.245 63.605 166.445 64.335 ;
      RECT 166.745 63.605 166.945 64.335 ;
      RECT 167.24 63.605 167.44 64.335 ;
      RECT 168.06 63.605 168.26 64.335 ;
      RECT 168.555 63.605 168.755 64.335 ;
      RECT 169.055 63.605 169.255 64.335 ;
      RECT 169.555 63.605 169.755 64.335 ;
      RECT 169.72 0.52 169.98 14.11 ;
      RECT 171.095 0.17 171.865 0.94 ;
      RECT 171.605 0.17 171.865 8.7 ;
      RECT 171.095 0.17 171.355 12.9 ;
      RECT 170.05 63.605 170.25 64.335 ;
      RECT 170.87 63.605 171.07 64.335 ;
      RECT 172.115 0.17 172.885 0.43 ;
      RECT 172.625 0.17 172.885 10.48 ;
      RECT 172.115 0.17 172.375 10.99 ;
      RECT 171.365 63.605 171.565 64.335 ;
      RECT 171.865 63.605 172.065 64.335 ;
      RECT 172.365 63.605 172.565 64.335 ;
      RECT 172.86 63.605 173.06 64.335 ;
      RECT 174.155 0.17 174.925 0.43 ;
      RECT 174.155 0.17 174.415 11.5 ;
      RECT 174.665 0.17 174.925 11.5 ;
      RECT 173.68 63.605 173.88 64.335 ;
      RECT 174.175 63.605 174.375 64.335 ;
      RECT 175.175 0.17 175.945 0.94 ;
      RECT 175.175 0.17 175.435 12.9 ;
      RECT 175.685 0.17 175.945 12.9 ;
      RECT 174.675 63.605 174.875 64.335 ;
      RECT 175.175 63.605 175.375 64.335 ;
      RECT 175.67 63.605 175.87 64.335 ;
      RECT 177.05 0.52 177.31 5.16 ;
      RECT 177.05 4.9 177.83 5.16 ;
      RECT 177.57 4.9 177.83 6.64 ;
      RECT 176.49 63.605 176.69 64.335 ;
      RECT 176.985 63.605 177.185 64.335 ;
      RECT 177.485 63.605 177.685 64.335 ;
      RECT 177.985 63.605 178.185 64.335 ;
      RECT 178.48 63.605 178.68 64.335 ;
      RECT 179.3 63.605 179.5 64.335 ;
      RECT 179.795 63.605 179.995 64.335 ;
      RECT 180.295 63.605 180.495 64.335 ;
      RECT 180.795 63.605 180.995 64.335 ;
      RECT 180.96 0.52 181.22 14.11 ;
      RECT 182.335 0.17 183.105 0.94 ;
      RECT 182.845 0.17 183.105 8.7 ;
      RECT 182.335 0.17 182.595 12.9 ;
      RECT 181.29 63.605 181.49 64.335 ;
      RECT 182.11 63.605 182.31 64.335 ;
      RECT 183.355 0.17 184.125 0.43 ;
      RECT 183.865 0.17 184.125 10.48 ;
      RECT 183.355 0.17 183.615 10.99 ;
      RECT 182.605 63.605 182.805 64.335 ;
      RECT 183.105 63.605 183.305 64.335 ;
      RECT 183.605 63.605 183.805 64.335 ;
      RECT 184.1 63.605 184.3 64.335 ;
      RECT 185.395 0.17 186.165 0.43 ;
      RECT 185.395 0.17 185.655 11.5 ;
      RECT 185.905 0.17 186.165 11.5 ;
      RECT 184.92 63.605 185.12 64.335 ;
      RECT 185.415 63.605 185.615 64.335 ;
      RECT 186.415 0.17 187.185 0.94 ;
      RECT 186.415 0.17 186.675 12.9 ;
      RECT 186.925 0.17 187.185 12.9 ;
      RECT 185.915 63.605 186.115 64.335 ;
      RECT 186.415 63.605 186.615 64.335 ;
      RECT 186.91 63.605 187.11 64.335 ;
      RECT 188.29 0.52 188.55 5.16 ;
      RECT 188.29 4.9 189.07 5.16 ;
      RECT 188.81 4.9 189.07 6.64 ;
      RECT 187.73 63.605 187.93 64.335 ;
      RECT 188.225 63.605 188.425 64.335 ;
      RECT 188.725 63.605 188.925 64.335 ;
      RECT 189.225 63.605 189.425 64.335 ;
      RECT 189.72 63.605 189.92 64.335 ;
      RECT 190.54 63.605 190.74 64.335 ;
      RECT 191.035 63.605 191.235 64.335 ;
      RECT 191.535 63.605 191.735 64.335 ;
      RECT 192.035 63.605 192.235 64.335 ;
      RECT 192.2 0.52 192.46 14.11 ;
      RECT 193.575 0.17 194.345 0.94 ;
      RECT 194.085 0.17 194.345 8.7 ;
      RECT 193.575 0.17 193.835 12.9 ;
      RECT 192.53 63.605 192.73 64.335 ;
      RECT 193.35 63.605 193.55 64.335 ;
      RECT 194.595 0.17 195.365 0.43 ;
      RECT 195.105 0.17 195.365 10.48 ;
      RECT 194.595 0.17 194.855 10.99 ;
      RECT 193.845 63.605 194.045 64.335 ;
      RECT 194.345 63.605 194.545 64.335 ;
      RECT 194.845 63.605 195.045 64.335 ;
      RECT 195.34 63.605 195.54 64.335 ;
      RECT 196.635 0.17 197.405 0.43 ;
      RECT 196.635 0.17 196.895 11.5 ;
      RECT 197.145 0.17 197.405 11.5 ;
      RECT 196.16 63.605 196.36 64.335 ;
      RECT 196.655 63.605 196.855 64.335 ;
      RECT 197.655 0.17 198.425 0.94 ;
      RECT 197.655 0.17 197.915 12.9 ;
      RECT 198.165 0.17 198.425 12.9 ;
      RECT 197.155 63.605 197.355 64.335 ;
      RECT 197.655 63.605 197.855 64.335 ;
      RECT 198.15 63.605 198.35 64.335 ;
      RECT 199.53 0.52 199.79 5.16 ;
      RECT 199.53 4.9 200.31 5.16 ;
      RECT 200.05 4.9 200.31 6.64 ;
      RECT 198.97 63.605 199.17 64.335 ;
      RECT 199.465 63.605 199.665 64.335 ;
      RECT 199.965 63.605 200.165 64.335 ;
      RECT 200.465 63.605 200.665 64.335 ;
      RECT 200.96 63.605 201.16 64.335 ;
      RECT 201.78 63.605 201.98 64.335 ;
      RECT 202.275 63.605 202.475 64.335 ;
      RECT 202.775 63.605 202.975 64.335 ;
      RECT 203.275 63.605 203.475 64.335 ;
      RECT 203.44 0.52 203.7 14.11 ;
      RECT 204.815 0.17 205.585 0.94 ;
      RECT 205.325 0.17 205.585 8.7 ;
      RECT 204.815 0.17 205.075 12.9 ;
      RECT 203.77 63.605 203.97 64.335 ;
      RECT 204.59 63.605 204.79 64.335 ;
      RECT 205.835 0.17 206.605 0.43 ;
      RECT 206.345 0.17 206.605 10.48 ;
      RECT 205.835 0.17 206.095 10.99 ;
      RECT 205.085 63.605 205.285 64.335 ;
      RECT 205.585 63.605 205.785 64.335 ;
      RECT 206.085 63.605 206.285 64.335 ;
      RECT 206.58 63.605 206.78 64.335 ;
      RECT 207.875 0.17 208.645 0.43 ;
      RECT 207.875 0.17 208.135 11.5 ;
      RECT 208.385 0.17 208.645 11.5 ;
      RECT 207.4 63.605 207.6 64.335 ;
      RECT 207.895 63.605 208.095 64.335 ;
      RECT 208.895 0.17 209.665 0.94 ;
      RECT 208.895 0.17 209.155 12.9 ;
      RECT 209.405 0.17 209.665 12.9 ;
      RECT 208.395 63.605 208.595 64.335 ;
      RECT 208.895 63.605 209.095 64.335 ;
      RECT 209.39 63.605 209.59 64.335 ;
      RECT 210.77 0.52 211.03 5.16 ;
      RECT 210.77 4.9 211.55 5.16 ;
      RECT 211.29 4.9 211.55 6.64 ;
      RECT 210.21 63.605 210.41 64.335 ;
      RECT 210.705 63.605 210.905 64.335 ;
      RECT 211.205 63.605 211.405 64.335 ;
      RECT 211.705 63.605 211.905 64.335 ;
      RECT 212.2 63.605 212.4 64.335 ;
      RECT 213.02 63.605 213.22 64.335 ;
      RECT 213.515 63.605 213.715 64.335 ;
      RECT 214.015 63.605 214.215 64.335 ;
      RECT 214.515 63.605 214.715 64.335 ;
      RECT 214.68 0.52 214.94 14.11 ;
      RECT 216.055 0.17 216.825 0.94 ;
      RECT 216.565 0.17 216.825 8.7 ;
      RECT 216.055 0.17 216.315 12.9 ;
      RECT 215.01 63.605 215.21 64.335 ;
      RECT 215.83 63.605 216.03 64.335 ;
      RECT 217.075 0.17 217.845 0.43 ;
      RECT 217.585 0.17 217.845 10.48 ;
      RECT 217.075 0.17 217.335 10.99 ;
      RECT 216.325 63.605 216.525 64.335 ;
      RECT 216.825 63.605 217.025 64.335 ;
      RECT 217.325 63.605 217.525 64.335 ;
      RECT 217.82 63.605 218.02 64.335 ;
      RECT 219.115 0.17 219.885 0.43 ;
      RECT 219.115 0.17 219.375 11.5 ;
      RECT 219.625 0.17 219.885 11.5 ;
      RECT 218.64 63.605 218.84 64.335 ;
      RECT 219.135 63.605 219.335 64.335 ;
      RECT 220.135 0.17 220.905 0.94 ;
      RECT 220.135 0.17 220.395 12.9 ;
      RECT 220.645 0.17 220.905 12.9 ;
      RECT 219.635 63.605 219.835 64.335 ;
      RECT 220.135 63.605 220.335 64.335 ;
      RECT 220.63 63.605 220.83 64.335 ;
      RECT 222.01 0.52 222.27 5.16 ;
      RECT 222.01 4.9 222.79 5.16 ;
      RECT 222.53 4.9 222.79 6.64 ;
      RECT 221.45 63.605 221.65 64.335 ;
      RECT 221.945 63.605 222.145 64.335 ;
      RECT 222.445 63.605 222.645 64.335 ;
      RECT 222.945 63.605 223.145 64.335 ;
      RECT 223.44 63.605 223.64 64.335 ;
      RECT 224.26 63.605 224.46 64.335 ;
      RECT 224.755 63.605 224.955 64.335 ;
      RECT 225.255 63.605 225.455 64.335 ;
      RECT 225.755 63.605 225.955 64.335 ;
      RECT 225.92 0.52 226.18 14.11 ;
      RECT 227.295 0.17 228.065 0.94 ;
      RECT 227.805 0.17 228.065 8.7 ;
      RECT 227.295 0.17 227.555 12.9 ;
      RECT 226.25 63.605 226.45 64.335 ;
      RECT 227.07 63.605 227.27 64.335 ;
      RECT 228.315 0.17 229.085 0.43 ;
      RECT 228.825 0.17 229.085 10.48 ;
      RECT 228.315 0.17 228.575 10.99 ;
      RECT 227.565 63.605 227.765 64.335 ;
      RECT 228.065 63.605 228.265 64.335 ;
      RECT 228.565 63.605 228.765 64.335 ;
      RECT 229.06 63.605 229.26 64.335 ;
      RECT 230.355 0.17 231.125 0.43 ;
      RECT 230.355 0.17 230.615 11.5 ;
      RECT 230.865 0.17 231.125 11.5 ;
      RECT 229.88 63.605 230.08 64.335 ;
      RECT 230.375 63.605 230.575 64.335 ;
      RECT 231.375 0.17 232.145 0.94 ;
      RECT 231.375 0.17 231.635 12.9 ;
      RECT 231.885 0.17 232.145 12.9 ;
      RECT 230.875 63.605 231.075 64.335 ;
      RECT 231.375 63.605 231.575 64.335 ;
      RECT 231.87 63.605 232.07 64.335 ;
      RECT 233.25 0.52 233.51 5.16 ;
      RECT 233.25 4.9 234.03 5.16 ;
      RECT 233.77 4.9 234.03 6.64 ;
      RECT 232.69 63.605 232.89 64.335 ;
      RECT 233.185 63.605 233.385 64.335 ;
      RECT 233.685 63.605 233.885 64.335 ;
      RECT 234.185 63.605 234.385 64.335 ;
      RECT 234.68 63.605 234.88 64.335 ;
      RECT 235.5 63.605 235.7 64.335 ;
      RECT 236.495 45.465 236.695 64.335 ;
    LAYER Metal2 SPACING 0.21 ;
      RECT 116.65 0 120.97 64.36 ;
      RECT 89.82 0 112.3 64.36 ;
      RECT 113.59 0 113.83 64.36 ;
      RECT 125.31 0 134.23 64.36 ;
      RECT 0 0 3.03 64.36 ;
      RECT 3.81 0 10.36 64.36 ;
      RECT 11.14 0 14.27 64.36 ;
      RECT 15.05 0 21.6 64.36 ;
      RECT 22.38 0 25.51 64.36 ;
      RECT 26.29 0 32.84 64.36 ;
      RECT 33.62 0 36.75 64.36 ;
      RECT 37.53 0 44.08 64.36 ;
      RECT 44.86 0 47.99 64.36 ;
      RECT 48.77 0 55.32 64.36 ;
      RECT 56.1 0 59.23 64.36 ;
      RECT 60.01 0 66.56 64.36 ;
      RECT 67.34 0 70.47 64.36 ;
      RECT 71.25 0 77.8 64.36 ;
      RECT 78.58 0 81.71 64.36 ;
      RECT 82.49 0 89.04 64.36 ;
      RECT 89.82 0.3 112.31 64.36 ;
      RECT 113.58 0.3 113.84 64.36 ;
      RECT 115.11 0 115.37 64.36 ;
      RECT 116.65 0.17 120.98 64.36 ;
      RECT 116.64 0.3 120.98 64.36 ;
      RECT 121.74 0 122 64.36 ;
      RECT 122.76 0 123.53 64.36 ;
      RECT 124.29 0 124.55 64.36 ;
      RECT 125.31 0.3 134.24 64.36 ;
      RECT 135.01 0 146.98 64.36 ;
      RECT 135 0.17 146.98 64.36 ;
      RECT 147.76 0 154.31 64.36 ;
      RECT 155.09 0 158.22 64.36 ;
      RECT 159 0 165.55 64.36 ;
      RECT 166.33 0 169.46 64.36 ;
      RECT 170.24 0 176.79 64.36 ;
      RECT 177.57 0 180.7 64.36 ;
      RECT 181.48 0 188.03 64.36 ;
      RECT 188.81 0 191.94 64.36 ;
      RECT 192.72 0 199.27 64.36 ;
      RECT 200.05 0 203.18 64.36 ;
      RECT 203.96 0 210.51 64.36 ;
      RECT 211.29 0 214.42 64.36 ;
      RECT 215.2 0 221.75 64.36 ;
      RECT 222.53 0 225.66 64.36 ;
      RECT 226.44 0 232.99 64.36 ;
      RECT 233.77 0 236.8 64.36 ;
      RECT 0 0.52 236.8 64.36 ;
    LAYER Metal3 ;
      RECT 0 0 236.8 64.36 ;
    LAYER Metal4 SPACING 0.21 ;
      RECT 12.95 39.085 20.86 45.205 ;
      RECT 12.95 0 15.24 64.36 ;
      RECT 18.57 0 20.86 64.36 ;
      RECT 24.19 39.085 32.1 45.205 ;
      RECT 24.19 0 26.48 64.36 ;
      RECT 29.81 0 32.1 64.36 ;
      RECT 35.43 39.085 43.34 45.205 ;
      RECT 35.43 0 37.72 64.36 ;
      RECT 41.05 0 43.34 64.36 ;
      RECT 46.67 39.085 54.58 45.205 ;
      RECT 46.67 0 48.96 64.36 ;
      RECT 52.29 0 54.58 64.36 ;
      RECT 57.91 39.085 65.82 45.205 ;
      RECT 57.91 0 60.2 64.36 ;
      RECT 63.53 0 65.82 64.36 ;
      RECT 69.15 39.085 77.06 45.205 ;
      RECT 69.15 0 71.44 64.36 ;
      RECT 74.77 0 77.06 64.36 ;
      RECT 80.39 39.085 88.3 45.205 ;
      RECT 80.39 0 82.68 64.36 ;
      RECT 86.01 0 88.3 64.36 ;
      RECT 91.63 0 98.71 64.36 ;
      RECT 102.04 0 103.86 64.36 ;
      RECT 107.19 0 109.01 64.36 ;
      RECT 112.34 0 114.16 64.36 ;
      RECT 117.49 0 119.31 64.36 ;
      RECT 122.64 0 124.46 64.36 ;
      RECT 148.5 39.085 156.41 45.205 ;
      RECT 148.5 0 150.79 64.36 ;
      RECT 154.12 0 156.41 64.36 ;
      RECT 159.74 39.085 167.65 45.205 ;
      RECT 159.74 0 162.03 64.36 ;
      RECT 165.36 0 167.65 64.36 ;
      RECT 170.98 39.085 178.89 45.205 ;
      RECT 170.98 0 173.27 64.36 ;
      RECT 176.6 0 178.89 64.36 ;
      RECT 182.22 39.085 190.13 45.205 ;
      RECT 182.22 0 184.51 64.36 ;
      RECT 187.84 0 190.13 64.36 ;
      RECT 193.46 39.085 201.37 45.205 ;
      RECT 0 39.085 9.62 45.205 ;
      RECT 0 0 4 64.36 ;
      RECT 7.33 0 9.62 64.36 ;
      RECT 193.46 0 195.75 64.36 ;
      RECT 199.08 0 201.37 64.36 ;
      RECT 204.7 39.085 212.61 45.205 ;
      RECT 204.7 0 206.99 64.36 ;
      RECT 210.32 0 212.61 64.36 ;
      RECT 215.94 39.085 223.85 45.205 ;
      RECT 215.94 0 218.23 64.36 ;
      RECT 221.56 0 223.85 64.36 ;
      RECT 227.18 39.085 236.8 45.205 ;
      RECT 227.18 0 229.47 64.36 ;
      RECT 232.8 0 236.8 64.36 ;
      RECT 127.79 0 129.61 64.36 ;
      RECT 132.94 0 134.76 64.36 ;
      RECT 138.09 0 145.17 64.36 ;
  END
END RM_IHPSG13_1P_64x16_c2

END LIBRARY
